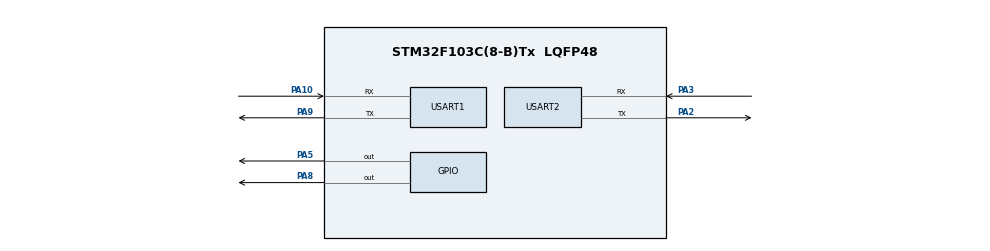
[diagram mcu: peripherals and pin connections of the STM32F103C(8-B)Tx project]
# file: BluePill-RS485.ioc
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Mcu.Family=STM32F1
Mcu.Name=STM32F103C(8-B)Tx
Mcu.Package=LQFP48
NVIC.PriorityGroup=NVIC_PRIORITYGROUP_4
NVIC.USART1_IRQn=true\:0\:0\:false\:false\:true\:true\:true
NVIC.USART2_IRQn=true\:0\:0\:false\:false\:true\:true\:true
PA10.Mode=Asynchronous
PA10.Signal=USART1_RX
PA2.Mode=Asynchronous
PA2.Signal=USART2_TX
PA3.Mode=Asynchronous
PA3.Signal=USART2_RX
PA5.Signal=GPIO_Output
PA8.Signal=GPIO_Output
PA9.Mode=Asynchronous
PA9.Signal=USART1_TX
ProjectManager.HeapSize=0x200
ProjectManager.StackSize=0x400
ProjectManager.TargetToolchain=TrueSTUDIO
RCC.APB1Freq_Value=8000000
RCC.APB2Freq_Value=8000000
USART1.VirtualMode=VM_ASYNC
USART2.VirtualMode=VM_ASYNC
VP_SYS_VS_ND.Mode=No_Debug
board=custom

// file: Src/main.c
/* USER CODE BEGIN Header */
/**
  ******************************************************************************
  * @file           : main.c
  * @brief          : Main program body
  ******************************************************************************
  * @attention
  *
  * <h2><center>&copy; Copyright (c) 2019 STMicroelectronics.
  * All rights reserved.</center></h2>
  *
  * This software component is licensed by ST under BSD 3-Clause license,
  * the "License"; You may not use this file except in compliance with the
  * License. You may obtain a copy of the License at:
  *                        opensource.org/licenses/BSD-3-Clause
  *
  ******************************************************************************
  */
/* USER CODE END Header */

#include "main.h"

/* USER CODE BEGIN PD */
#define TXSTARTMESSAGESIZE                   (COUNTOF(StartMessagge) - 1)
#define RXBUFFERSIZE							1
#define COUNTOF(__BUFFER__)   (sizeof(__BUFFER__) / sizeof(*(__BUFFER__)))

/* USER CODE END PD */

UART_HandleTypeDef huart1;
UART_HandleTypeDef huart2;

/* USER CODE BEGIN PV */
uint8_t StartMessagge[] = "\r\n Uart Ready: \r\n ";
uint8_t aRxBuffer[RXBUFFERSIZE];
uint8_t return_value;

/* USER CODE END PV */

void SystemClock_Config(void);
static void MX_GPIO_Init(void);
static void MX_USART1_UART_Init(void);
static void MX_USART2_UART_Init(void);
/* USER CODE BEGIN PFP */
void set_transmit_mode_uart1(void)
{
    HAL_GPIO_WritePin(GPIOB, GPIO_PIN_15, GPIO_PIN_SET);  // RS 485 transmit mode
}

void set_receive_mode_uart1(void)
{
    HAL_GPIO_WritePin(GPIOB, GPIO_PIN_15, GPIO_PIN_RESET); // RS 485 receive mode
}
void set_transmit_mode_uart2(void)
{
    HAL_GPIO_WritePin(GPIOB, GPIO_PIN_14, GPIO_PIN_SET);  // RS 485 transmit mode
}

void set_receive_mode_uart2(void)
{
    HAL_GPIO_WritePin(GPIOB, GPIO_PIN_14, GPIO_PIN_RESET); // RS 485 receive mode
}
/* USER CODE END PFP */

int main(void)
{

  /* MCU Configuration--------------------------------------------------------*/

  /* Reset of all peripherals, Initializes the Flash interface and the Systick. */
  HAL_Init();

  /* Configure the system clock */
  SystemClock_Config();

  /* Initialize all configured peripherals */
  MX_GPIO_Init();
  MX_USART1_UART_Init();
  MX_USART2_UART_Init();
  /* USER CODE BEGIN 2 */
//  __HAL_UART_ENABLE_IT(&huart1, UART_IT_RXNE);
//  __HAL_UART_ENABLE_IT(&huart1, UART_IT_TC);
//  __HAL_UART_ENABLE_IT(&huart2, UART_IT_RXNE);
//  __HAL_UART_ENABLE_IT(&huart2, UART_IT_TC);
      set_transmit_mode_uart1();
//      HAL_Delay(10);
////      return_value =
//    		  HAL_UART_Transmit_IT(&huart1,StartMessagge,TXSTARTMESSAGESIZE);
//      HAL_Delay(500);
//      if (return_value == HAL_OK)
//      {
//      	//Success
//      }
//      else
//      {
//      }

  set_transmit_mode_uart2();
  while(1);
  HAL_Delay(10);
//  return_value =
		  HAL_UART_Transmit_IT(&huart2,StartMessagge,TXSTARTMESSAGESIZE);
//  if (return_value == HAL_OK)
//  {
//  	//Success
//  }
//  else
//  {
//  }
  HAL_Delay(10);

//  set_receive_mode_uart1();
  set_receive_mode_uart1();
  HAL_UART_Receive_IT(&huart1, aRxBuffer, RXBUFFERSIZE);
//  set_receive_mode_uart2();
  set_receive_mode_uart2();
  HAL_UART_Receive_IT(&huart2, aRxBuffer, RXBUFFERSIZE);
  /* USER CODE END 2 */

  /* Infinite loop */
  while (1)
  {

  }
}

void SystemClock_Config(void)
{
  RCC_OscInitTypeDef RCC_OscInitStruct = {0};
  RCC_ClkInitTypeDef RCC_ClkInitStruct = {0};

  /** Initializes the CPU, AHB and APB busses clocks
  */
  RCC_OscInitStruct.OscillatorType = RCC_OSCILLATORTYPE_HSI;
  RCC_OscInitStruct.HSIState = RCC_HSI_ON;
  RCC_OscInitStruct.HSICalibrationValue = RCC_HSICALIBRATION_DEFAULT;
  RCC_OscInitStruct.PLL.PLLState = RCC_PLL_NONE;
  if (HAL_RCC_OscConfig(&RCC_OscInitStruct) != HAL_OK)
  {
    Error_Handler();
  }
  /** Initializes the CPU, AHB and APB busses clocks
  */
  RCC_ClkInitStruct.ClockType = RCC_CLOCKTYPE_HCLK|RCC_CLOCKTYPE_SYSCLK
                              |RCC_CLOCKTYPE_PCLK1|RCC_CLOCKTYPE_PCLK2;
  RCC_ClkInitStruct.SYSCLKSource = RCC_SYSCLKSOURCE_HSI;
  RCC_ClkInitStruct.AHBCLKDivider = RCC_SYSCLK_DIV1;
  RCC_ClkInitStruct.APB1CLKDivider = RCC_HCLK_DIV1;
  RCC_ClkInitStruct.APB2CLKDivider = RCC_HCLK_DIV1;

  if (HAL_RCC_ClockConfig(&RCC_ClkInitStruct, FLASH_LATENCY_0) != HAL_OK)
  {
    Error_Handler();
  }
}

static void MX_USART1_UART_Init(void)
{

  huart1.Instance = USART1;
  huart1.Init.BaudRate = 115200;
  huart1.Init.WordLength = UART_WORDLENGTH_8B;
  huart1.Init.StopBits = UART_STOPBITS_1;
  huart1.Init.Parity = UART_PARITY_NONE;
  huart1.Init.Mode = UART_MODE_TX_RX;
  huart1.Init.HwFlowCtl = UART_HWCONTROL_NONE;
  huart1.Init.OverSampling = UART_OVERSAMPLING_16;
  if (HAL_UART_Init(&huart1) != HAL_OK)
  {
    Error_Handler();
  }

}

static void MX_USART2_UART_Init(void)
{

  huart2.Instance = USART2;
  huart2.Init.BaudRate = 115200;
  huart2.Init.WordLength = UART_WORDLENGTH_8B;
  huart2.Init.StopBits = UART_STOPBITS_1;
  huart2.Init.Parity = UART_PARITY_NONE;
  huart2.Init.Mode = UART_MODE_TX_RX;
  huart2.Init.HwFlowCtl = UART_HWCONTROL_NONE;
  huart2.Init.OverSampling = UART_OVERSAMPLING_16;
  if (HAL_UART_Init(&huart2) != HAL_OK)
  {
    Error_Handler();
  }

}

static void MX_GPIO_Init(void)
{
  GPIO_InitTypeDef GPIO_InitStruct = {0};

  /* GPIO Ports Clock Enable */
  __HAL_RCC_GPIOC_CLK_ENABLE();
  __HAL_RCC_GPIOA_CLK_ENABLE();
  __HAL_RCC_GPIOB_CLK_ENABLE();

  /*Configure GPIO pin Output Level */
  HAL_GPIO_WritePin(GPIOB, GPIO_PIN_14, GPIO_PIN_SET);

  /*Configure GPIO pin Output Level */
  HAL_GPIO_WritePin(GPIOB, GPIO_PIN_15, GPIO_PIN_SET);

  /*Configure GPIO pin : PC13 */
  GPIO_InitStruct.Pin = GPIO_PIN_14;
  GPIO_InitStruct.Mode = GPIO_MODE_OUTPUT_PP;
  GPIO_InitStruct.Pull = GPIO_NOPULL;
  GPIO_InitStruct.Speed = GPIO_SPEED_FREQ_LOW;
  HAL_GPIO_Init(GPIOC, &GPIO_InitStruct);

  /*Configure GPIO pin : PB15 */
  GPIO_InitStruct.Pin = GPIO_PIN_15;
  GPIO_InitStruct.Mode = GPIO_MODE_OUTPUT_PP;
  GPIO_InitStruct.Pull = GPIO_NOPULL;
  GPIO_InitStruct.Speed = GPIO_SPEED_FREQ_LOW;
  HAL_GPIO_Init(GPIOB, &GPIO_InitStruct);

}

/* USER CODE BEGIN 4 */
void HAL_UART_TxCpltCallback(UART_HandleTypeDef *UartHandle)
{
//	if (UartHandle==&huart1)
//	{
//		set_receive_mode_uart2();
//		set_receive_mode_uart2();
//		HAL_UART_Receive_IT(&huart2, aRxBuffer, RXBUFFERSIZE);
//	}
//	if (UartHandle==&huart2)
//	{
//		set_receive_mode_uart1();
//		set_receive_mode_uart1();
//		HAL_UART_Receive_IT(&huart1, aRxBuffer, RXBUFFERSIZE);
//	}
}
void HAL_UART_RxCpltCallback(UART_HandleTypeDef *UartHandle)
{
	if (UartHandle==&huart1)
	{
	set_transmit_mode_uart2();
	set_transmit_mode_uart2();
	HAL_UART_Transmit_IT(&huart2,aRxBuffer,RXBUFFERSIZE);

	}
	if (UartHandle==&huart2)
	{
	set_transmit_mode_uart1();
	set_transmit_mode_uart1();
	HAL_UART_Transmit_IT(&huart1,aRxBuffer,RXBUFFERSIZE);
	}
}
/* USER CODE END 4 */

void Error_Handler(void)
{
}

/************************ (C) COPYRIGHT STMicroelectronics *****END OF FILE****/
